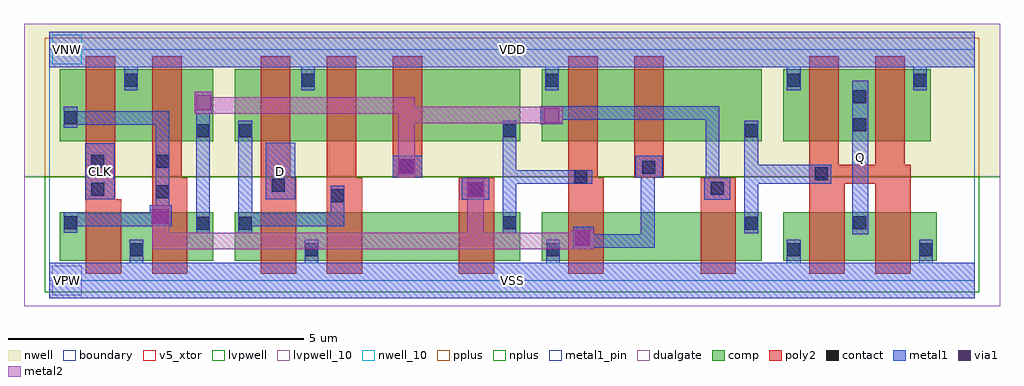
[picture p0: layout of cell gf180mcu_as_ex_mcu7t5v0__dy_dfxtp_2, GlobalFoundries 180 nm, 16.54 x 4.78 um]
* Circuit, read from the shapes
.subckt gf180mcu_as_ex_mcu7t5v0__dy_dfxtp_2 CLK D Q VDD VNW VSS
XM1 VSS CLK n1 VSUBS nfet_05v0 w=0.82u l=0.6u
XM2 n2 n1 VSS VSUBS nfet_05v0 w=0.82u l=0.6u
XM3 VSS D n3 VSUBS nfet_05v0 w=0.82u l=0.6u
XM4 n4 n3 VSS VSUBS nfet_05v0 w=0.82u l=0.6u
XM5 n5 n1 n4 VSUBS nfet_05v0 w=0.82u l=0.6u
XM6 n6 n5 VSS VSUBS nfet_05v0 w=0.82u l=0.6u
XM7 n7 n2 n6 VSUBS nfet_05v0 w=0.82u l=0.6u
XM8 Q n7 VSS VSUBS nfet_05v0 w=0.82u l=0.6u m=2
XM9 VDD CLK n1 VNW pfet_05v0 w=1.22u l=0.5u
XM10 n2 n1 VDD VNW pfet_05v0 w=1.22u l=0.5u
XM11 VDD D n3 VNW pfet_05v0 w=1.22u l=0.5u
XM12 n8 n3 VDD VNW pfet_05v0 w=1.22u l=0.5u
XM13 n5 n2 n8 VNW pfet_05v0 w=1.22u l=0.5u
XM14 n9 n5 VDD VNW pfet_05v0 w=1.22u l=0.5u
XM15 n7 n1 n9 VNW pfet_05v0 w=1.22u l=0.5u
XM16 Q n7 VDD VNW pfet_05v0 w=1.22u l=0.5u m=2
.ends

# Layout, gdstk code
import gdstk
lib = gdstk.Library(unit=1e-6, precision=1e-09)
def R(c, l, rs):  # rectangles x0, y0, x1, y1
    for r in rs: c.add(gdstk.rectangle(r[:2], r[2:], *l))
def A(c, l, x, y, w, h, nx, ny, dx, dy):  # array of equal rectangles
    R(c, l, [(x+i*dx, y+j*dy, x+i*dx+w, y+j*dy+h) for i in range(nx) for j in range(ny)])
boundary = (0, 0)
nwell = (21, 0)
nwell_10 = (21, 10)
comp = (22, 0)
poly2 = (30, 0)
pplus = (31, 0)
nplus = (32, 0)
contact = (33, 0)
metal1 = (34, 0)
metal1_pin = (34, 10)
via1 = (35, 0)
metal2 = (36, 0)
dualgate = (55, 0)
v5_xtor = (112, 1)
lvpwell = (204, 0)
lvpwell_10 = (204, 10)

gf180mcu_as_ex_mcu7t5v0_ = lib.new_cell('gf180mcu_as_ex_mcu7t5v0__dy_dfxtp_2')
R(gf180mcu_as_ex_mcu7t5v0_, boundary, [(0,0,15.68,3.92)])
R(gf180mcu_as_ex_mcu7t5v0_, nwell, [(-0.43,1.76,16.11,4.35)])
R(gf180mcu_as_ex_mcu7t5v0_, nwell_10, [(0.05,3.67,0.55,4.17)])
R(gf180mcu_as_ex_mcu7t5v0_, comp, [(0.18,0.34,2.78,1.16), (3.14,0.34,7.98,1.16), (8.34,0.34,12.075,1.16), (12.435,0.34,15.035,1.16), (0.18,2.36,2.78,3.58), (3.14,2.36,7.98,3.58), (8.34,2.36,12.075,3.58), (12.435,2.36,14.935,3.58)])
A(gf180mcu_as_ex_mcu7t5v0_, poly2, 3.58, 1.745, 0.5, 2.055, 3, 1, 1.12, 0)
R(gf180mcu_as_ex_mcu7t5v0_, poly2, [(0.62,0.12,1.22,1.38), (1.74,0.12,2.34,1.745), (3.58,0.12,4.18,1.745), (4.7,0.12,5.3,1.745), (6.94,0.12,7.54,1.745), (8.795,0.12,9.395,1.745), (11.035,0.12,11.635,1.745), (12.875,0.12,13.475,1.64), (13.995,0.12,14.595,1.64), (0.62,1.38,1.12,3.8), (12.875,1.64,14.595,1.965), (1.74,1.745,2.24,3.8), (8.795,1.745,9.295,3.8), (9.915,1.745,10.415,3.8), (12.875,1.965,13.375,3.8), (13.995,1.965,14.495,3.8)])
R(gf180mcu_as_ex_mcu7t5v0_, pplus, [(-0.08,1.76,15.76,4.12), (0.39,2.13,2.47,2.2), (3.35,2.13,6.55,2.2), (8.565,2.13,10.645,2.2), (12.645,2.13,14.725,2.2), (0.02,2.2,15.095,3.74), (0.39,3.74,2.47,3.81), (3.35,3.74,6.55,3.81), (8.565,3.74,10.645,3.81), (12.645,3.74,14.725,3.81)])
R(gf180mcu_as_ex_mcu7t5v0_, nplus, [(-0.08,-0.2,15.76,1.76), (-0.08,-0.2,15.76,1.76)])
R(gf180mcu_as_ex_mcu7t5v0_, contact, [(1.37,0.41,1.59,0.63), (4.33,0.41,4.55,0.63), (8.425,0.41,8.645,0.63), (12.505,0.41,12.725,0.63), (14.745,0.41,14.965,0.63), (2.49,0.865,2.71,1.085), (3.21,0.865,3.43,1.085), (11.785,0.865,12.005,1.085), (0.25,0.87,0.47,1.09), (7.69,0.87,7.91,1.09), (13.625,0.87,13.845,1.09), (4.77,1.33,4.99,1.55), (1.81,1.4,2.03,1.62), (0.71,1.44,0.93,1.66), (7.12,1.44,7.34,1.66), (11.21,1.455,11.43,1.675), (3.765,1.505,3.985,1.725), (8.895,1.65,9.115,1.87), (12.97,1.7,13.19,1.92), (10.045,1.815,10.265,2.035), (5.935,1.825,6.155,2.045), (0.71,1.91,0.93,2.13), (1.81,1.915,2.03,2.135), (2.49,2.43,2.71,2.65), (3.21,2.43,3.43,2.65), (7.69,2.43,7.91,2.65), (11.785,2.43,12.005,2.65), (13.625,2.535,13.845,2.755), (0.25,2.65,0.47,2.87), (13.625,3.005,13.845,3.225), (1.27,3.29,1.49,3.51), (4.275,3.29,4.495,3.51), (8.41,3.29,8.63,3.51), (12.505,3.29,12.725,3.51), (14.645,3.29,14.865,3.51)])
R(gf180mcu_as_ex_mcu7t5v0_, metal1, [(0,-0.3,15.68,0.3), (1.365,0.3,1.595,0.69), (4.325,0.3,4.555,0.69), (8.42,0.3,8.65,0.69), (12.5,0.3,12.73,0.69), (14.74,0.3,14.97,0.69), (8.88,0.53,9.235,0.555), (8.88,0.555,10.255,0.785), (8.88,0.785,9.225,0.91), (10.025,0.785,10.255,1.745), (13.61,0.79,13.88,3.39), (2.485,0.805,2.715,2.825), (3.205,0.805,3.435,0.92), (7.685,0.805,7.915,1.645), (11.78,0.805,12.01,1.64), (0.245,0.81,0.475,0.92), (0.245,0.92,2.075,1.15), (3.205,0.92,4.995,1.15), (0.245,1.15,0.475,1.16), (1.705,1.15,2.075,1.275), (3.205,1.15,3.435,2.71), (4.765,1.15,4.995,1.61), (1.805,1.275,2.035,2.645), (6.99,1.37,7.455,1.745), (11.095,1.37,11.535,1.745), (0.61,1.38,1.11,2.33), (3.665,1.38,4.17,2.335), (11.78,1.64,13.25,1.965), (7.685,1.645,9.2,1.875), (5.82,1.745,6.32,2.12), (9.93,1.745,10.395,2.12), (11.125,1.745,11.355,2.725), (7.685,1.875,7.915,2.71), (11.78,1.965,12.01,2.71), (0.245,2.59,0.475,2.645), (0.245,2.645,2.035,2.875), (8.32,2.65,8.7,2.725), (8.32,2.725,11.355,2.955), (2.465,2.825,2.755,3.205), (0.245,2.875,0.475,2.95), (1.265,3.23,1.495,3.62), (4.27,3.23,4.5,3.62), (8.405,3.23,8.635,3.62), (12.5,3.23,12.73,3.62), (14.64,3.23,14.87,3.62), (0,3.62,15.68,4.22)])
R(gf180mcu_as_ex_mcu7t5v0_, metal1_pin, [(0,-0.3,15.68,0.3), (13.61,0.79,13.88,3.39), (0.61,1.38,1.11,2.33), (3.665,1.38,4.17,2.335), (0,3.62,15.68,4.22)])
R(gf180mcu_as_ex_mcu7t5v0_, via1, [(8.905,0.59,9.165,0.85), (1.755,0.96,2.015,1.22), (7.1,1.415,7.36,1.675), (5.93,1.805,6.19,2.065), (8.38,2.665,8.64,2.925), (2.485,2.885,2.745,3.145)])
R(gf180mcu_as_ex_mcu7t5v0_, metal2, [(1.74,0.53,9.23,0.81), (1.74,0.81,2.03,0.935), (7.085,0.81,7.365,1.4), (8.845,0.81,9.23,0.86), (1.735,0.935,2.03,1.28), (7.085,1.4,7.37,1.735), (5.915,1.745,6.2,2.125), (5.915,2.125,6.195,2.665), (8.36,2.655,8.7,2.665), (5.915,2.665,8.7,2.83), (2.465,2.825,2.755,2.83), (2.465,2.83,8.7,2.945), (2.465,2.945,6.195,3.11), (2.465,3.11,2.755,3.205)])
R(gf180mcu_as_ex_mcu7t5v0_, dualgate, [(-0.43,-0.43,16.11,4.35), (0.22,-0.06,2.74,0.1), (3.18,-0.06,5.7,0.1), (6.54,-0.06,7.94,0.1), (8.395,-0.06,9.795,0.1), (10.635,-0.06,12.035,0.1), (12.475,-0.06,14.995,0.1), (-0.06,0.1,15.275,1.4), (0.22,1.4,2.74,1.56), (3.18,1.4,5.7,1.96), (6.54,1.4,7.94,1.56), (8.395,1.4,9.795,1.96), (10.635,1.4,12.035,1.56), (12.475,1.4,14.995,1.56), (0.22,1.56,2.64,2.12), (6.54,1.56,6.72,1.96), (10.635,1.56,10.815,1.96), (12.475,1.56,14.895,2.12), (3.18,1.96,6.72,2.12), (8.395,1.96,10.815,2.12), (-0.06,2.12,15.175,3.82), (0.22,3.82,2.64,3.98), (3.18,3.82,6.72,3.98), (8.395,3.82,10.815,3.98), (12.475,3.82,14.895,3.98)])
R(gf180mcu_as_ex_mcu7t5v0_, v5_xtor, [(-0.43,-0.43,16.11,4.35)])
R(gf180mcu_as_ex_mcu7t5v0_, lvpwell, [(-0.43,-0.43,16.11,1.76)])
R(gf180mcu_as_ex_mcu7t5v0_, lvpwell_10, [(0.05,-0.25,0.55,0.25)])
gf180mcu_as_ex_mcu7t5v0_.add(gdstk.Label('VDD', (7.84,3.92), layer=34, texttype=10))
gf180mcu_as_ex_mcu7t5v0_.add(gdstk.Label('VSS', (7.84,0), layer=34, texttype=10))
gf180mcu_as_ex_mcu7t5v0_.add(gdstk.Label('D', (3.917,1.857), layer=34, texttype=10))
gf180mcu_as_ex_mcu7t5v0_.add(gdstk.Label('Q', (13.745,2.09), layer=34, texttype=10))
gf180mcu_as_ex_mcu7t5v0_.add(gdstk.Label('CLK', (0.86,1.855), layer=34, texttype=10))
gf180mcu_as_ex_mcu7t5v0_.add(gdstk.Label('VNW', (0.3,3.92), layer=21, texttype=10))
gf180mcu_as_ex_mcu7t5v0_.add(gdstk.Label('VPW', (0.3,0), layer=204, texttype=10))

lib.write_gds('gf180mcu_as_ex_mcu7t5v0__dy_dfxtp_2.gds')
